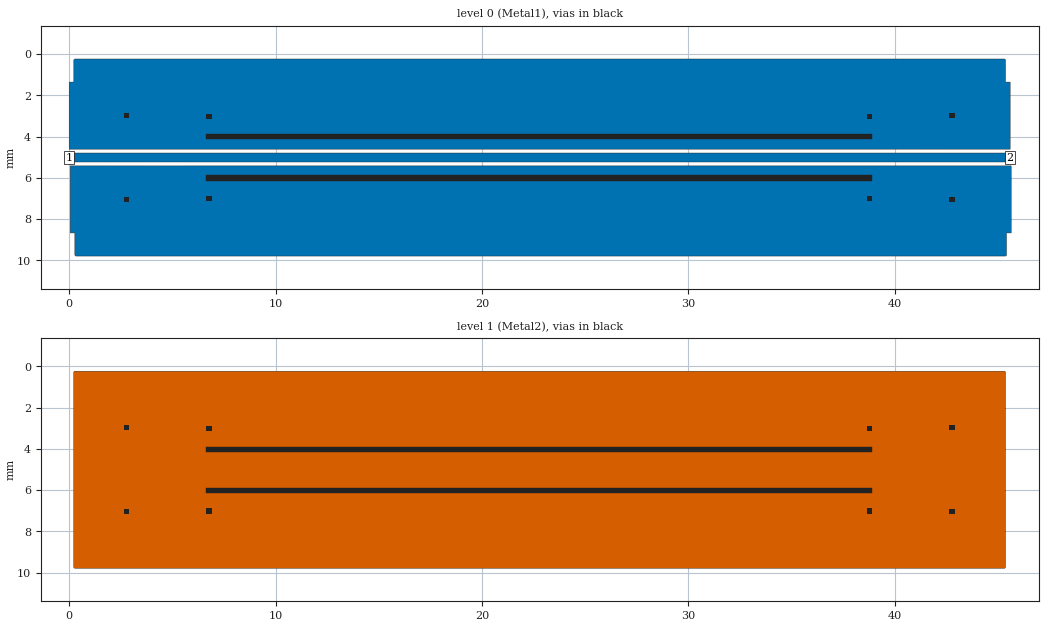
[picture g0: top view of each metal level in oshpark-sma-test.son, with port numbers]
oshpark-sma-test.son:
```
FTYP SONPROJ 17 ! Sonnet Project File
VER 17.52.2
HEADER
LIC antikernel2.1.48685 90e2ba8817c0 havequick azonenberg
DAT 05/13/2020 22:04:07
BUILT_BY_CREATED dxf 17.52.2 05/01/2020 05:35:06
BUILT_BY_SAVED sonnet 17.52.2
MDATE 05/13/2020 22:04:07
HDATE 05/13/2020 22:04:07
ANN Created by dxfgeo, Sonnet Software Inc.
END HEADER
DIM
ANG DEG
CAP PF
CON /OH
FREQ GHZ
IND NH
LNG MM
RES OH
END DIM
CONTROL
VARSWP
OPTIONS  -dj
SPEED 1
CACHE_ABS 1
Q_ACC N
END CONTROL
GEO
SYM
TMET "Free Space" 0 FREESPACE 376.7303136 0 0 0
BMET "Free Space" 0 FREESPACE 376.7303136 0 0 0
MET "Unknown_metal" 1 NOR INF 0.5 0 
MET "Copper 1oz thick" 2 TMM 58000000 0.5 0.035 2
MET "Nickel " 3 TMM 14300000 0.5 0.035 2
MET "Copper 0.5oz" 1 NOR 58000000 0.5 0.017 
MET "Unknown_metal" 1 VOL INF 0
BRI "Alumina (96%)" 0 9.4 0.0004 0 
BRI "Alumina (99.5%)" 0 9.9 0.0001 0 
BRI "Aluminum Nitride" 0 8.6 0.0003 0 
BRI "Arlon 25FR" 0 3.58 0.0035 0 
BRI "Arlon 25N" 0 3.38 0.0025 0 
BRI "Arlon AD5" 0 5.1 0.003 0 
BRI "Arlon AD10" 0 10.2 0.005 0 
BRI "Arlon AD250" 0 2.5 0.0018 0 
BRI "Arlon AD255A" 0 2.55 0.0015 0 
BRI "Arlon AD260A" 0 2.6 0.0018 0 
BRI "Arlon AD270" 0 2.7 0.0023 0 
BRI "Arlon AD300A" 0 3 0.002 0 
BRI "Arlon AD320A" 0 3.2 0.0032 0 
BRI "Arlon AD350A" 0 3.5 0.003 0 
BRI "Arlon AD410" 0 4.1 0.003 0 
BRI "Arlon AD430" 0 4.3 0.003 0 
BRI "Arlon AD450" 0 4.5 0.0035 0 
BRI "Arlon AD600" 0 6.15 0.003 0 
BRI "Arlon AD1000" 0 10.2 0.0023 0 
BRI "Arlon AR1000" 0 9.8 0.003 0 
BRI "Arlon CLTE" 0 2.96 0.0023 0 
BRI "Arlon CLTE-AT" 0 3 0.0013 0 
BRI "Arlon CLTE-P" 0 2.94 0.0025 0 
BRI "Arlon CLTE-XT" 0 2.94 0.0012 0 
BRI "Arlon Cu 217LX" 0 2.17 0.0009 0 
BRI "Arlon Cu 233LX" 0 2.33 0.0013 0 
BRI "Arlon Cu 250GT" 0 2.5 0.001 0 
BRI "Arlon Cu 250GX" 0 2.5 0.0018 0 
BRI "Arlon Cu 6250" 0 2.32 0.0013 0 
BRI "Arlon Cu 6700" 0 2.35 0.0025 0 
BRI "Arlon Di 522" 0 2.5 0.001 0 
BRI "Arlon Di 527" 0 2.5 0.0018 0 
BRI "Arlon Di 870" 0 2.33 0.0013 0 
BRI "Arlon Di 880" 0 2.17 0.0009 0 
BRI "Arlon Iso 917" 0 2.17 0.0013 0 
BRI "Arlon Iso 933" 0 2.33 0.0016 0 
BRI "Arlon Multi HF" 0 3.7 0.004 0 
BRI "Arlon TC350" 0 3.5 0.002 0 
BRI "Arlon TC600" 0 6.15 0.002 0 
BRI "Beryllia (99.5%)" 0 6.5 0.0004 0 
BRI "CEM-1" 0 4.5 0.02 0 
BRI "CEM-3" 0 4.5 0.02 0 
BRI "Dupont 9K7" 0 7.1 0.0012 0 
BRI "Dupont 943" 0 7.4 0.002 0 
BRI "Dupont 951" 0 7.8 0.006 0 
BRI "Dupont FEP" 0 2 0.0005 0 
BRI "Dupont Vacrel" 0 3.8 0.011 0 
BRI "ESL 41010" 0 7.5 0.005 0 
BRI "ESL 41020" 0 7.25 0.005 0 
BRI "ESL 41050" 0 13.5 0.002 0 
BRI "ESL 41060" 0 16.5 0.002 0 
BRI "ESL 41110" 0 4.5 0.004 0 
BRI "Ferro A6M" 0 5.9 0.002 0 
BRI "Ferro A6S" 0 5.9 0.002 0 
BRI "Ferro L8" 0 7.3 0.0018 0 
BRI "FR-4" 0 4.4 0.02 0 
BRI "G-10" 0 4.8 0.025 0 
BRI "Gallium Arsenide" 0 12.9 0.006 0 
BRI "Gallium Nitride" 0 9.7 0 0 
BRI "Glass (Pyrex)" 0 4.82 0.0054 0 
BRI "Heraeus HL2000" 0 7.3 0.0026 0 
BRI "Isola 370HR" 0 4.04 0.021 0 
BRI "Isola FR408" 0 3.77 0.0116 0 
BRI "Isola FR408HR" 0 3.68 0.0092 0 
BRI "Isola Getek" 0 3.6 0.01 0 
BRI "Isola GI-180" 0 3.7 0.013 0 
BRI "Isola IS415" 0 3.82 0.0125 0 
BRI "Isola IS620i" 0 3.58 0.006 0 
BRI "Isola IS680-280" 0 2.8 0.0025 0 
BRI "Isola IS680-300" 0 3 0.003 0 
BRI "Isola IS680-320" 0 3.2 0.003 0 
BRI "Isola IS680-333" 0 3.33 0.003 0 
BRI "Isola IS680-338" 0 3.38 0.0032 0 
BRI "Isola IS680-345" 0 3.45 0.0036 0 
BRI "Kerafol CT800" 0 5.3 0.008 0 
BRI "Nelco MW9350" 0 3.7 0.004 0 
BRI "Nelco N4000-12" 0 3.7 0.008 0 
BRI "Nelco N4000-13" 0 3.7 0.009 0 
BRI "Nelco N4000-13SI" 0 3.2 0.007 0 
BRI "Nelco N4000-13EP" 0 3.7 0.008 0 
BRI "Nelco N4350-13RF" 0 3.5 0.0065 0 
BRI "Nelco N4380-13RF" 0 3.8 0.007 0 
BRI "Nelco N9300-13RF" 0 3 0.004 0 
BRI "Nelco N9320-13RF" 0 3.2 0.0045 0 
BRI "Nelco N9338-13RF" 0 3.38 0.0046 0 
BRI "Nelco N9350-13RF" 0 3.48 0.0055 0 
BRI "Nelco NH9294" 0 2.94 0.0022 0 
BRI "Nelco NH9300" 0 3 0.0023 0 
BRI "Nelco NH9320" 0 3.2 0.0024 0 
BRI "Nelco NH9338" 0 3.38 0.0025 0 
BRI "Nelco NH9348" 0 3.48 0.003 0 
BRI "Nelco NH9350" 0 3.5 0.003 0 
BRI "Nelco NH9410" 0 4.1 0.003 0 
BRI "Nelco NH9450" 0 4.5 0.003 0 
BRI "Nelco NX9240" 0 2.4 0.0016 0 
BRI "Nelco NX9245" 0 2.45 0.0016 0 
BRI "Nelco NX9250" 0 2.5 0.0017 0 
BRI "Nelco NX9255" 0 2.55 0.0018 0 
BRI "Nelco NX9260" 0 2.6 0.0019 0 
BRI "Nelco NY9208" 0 2.08 0.0006 0 
BRI "Nelco NY9217" 0 2.17 0.0008 0 
BRI "Nelco NY9220" 0 2.2 0.0009 0 
BRI "Nelco NY9233" 0 2.33 0.0011 0 
BRI "PET" 0 3.37 0.0208 0 
BRI "Polyimide" 0 3.5 0.003 0 
BRI "Quartz (Fused)" 0 3.78 0.0001 0 
BRI "Rogers 3001" 0 2.28 0.003 0 
BRI "Rogers RO2808" 0 7.6 0.0015 0 
BRI "Rogers RO3003" 0 3 0.0013 0 
BRI "Rogers RO3006" 0 6.5 0.002 0 
BRI "Rogers RO3010" 0 11.2 0.0022 0 
BRI "Rogers RO3035" 0 3.6 0.0018 0 
BRI "Rogers RO3203" 0 3.02 0.0016 0 
BRI "Rogers RO3206" 0 6.6 0.0027 0 
BRI "Rogers RO3210" 0 10.8 0.0027 0 
BRI "Rogers RO3730" 0 3 0.0016 0 
BRI "Rogers RO4003C" 0 3.55 0.0029 0 
BRI "Rogers RO4533" 0 3.45 0.0029 0 
BRI "Rogers RO4534" 0 3.4 0.003 0 
BRI "Rogers RO4350B" 0 3.66 0.0037 0 
BRI "Rogers RO4350BTX" 0 3.66 0.0034 0 
BRI "Rogers RO4360" 0 6.15 0.0038 0 
BRI "Rogers RO4450B-3.6" 0 3.3 0.0043 0 
BRI "Rogers RO4450B-4" 0 3.54 0.004 0 
BRI "Rogers RO4450F" 0 3.52 0.0041 0 
BRI "Rogers RO4730" 0 3 0.0033 0 
BRI "Rogers RT5870" 0 2.33 0.0012 0 
BRI "Rogers RT5880" 0 2.2 0.0009 0 
BRI "Rogers RT5880LZ" 0 1.96 0.0019 0 
BRI "Rogers RT6002" 0 2.94 0.0012 0 
BRI "Rogers RT6006" 0 6.15 0.0027 0 
BRI "Rogers RT6010LM" 0 10.9 0.0023 0 
BRI "Rogers RT6035HTC" 0 3.6 0.0013 0 
BRI "Rogers RT6202" 0 2.94 0.0015 0 
BRI "Rogers RT6202PR" 0 2.95 0.0015 0 
BRI "Rogers Syron7000" 0 3.4 0.0045 0 
BRI "Rogers Syron7100-2" 0 3.61 0.006 0 
BRI "Rogers Syron7100-4" 0 3.39 0.005 0 
BRI "Rogers Theta" 0 4.01 0.0118 0 
BRI "Rogers TMM 3" 0 3.39 0.002 0 
BRI "Rogers TMM 4" 0 4.5 0.002 0 
BRI "Rogers TMM 6" 0 6 0.0023 0 
BRI "Rogers TMM 10" 0 9.56 0.0022 0 
BRI "Rogers TMM 10i" 0 9.96 0.002 0 
BRI "Rogers UL2000" 0 2.5 0.0019 0 
BRI "Rogers UL3850" 0 3.05 0.0025 0 
BRI "Rogers UL3908" 0 2.9 0.0025 0 
BRI "Rogers XT8000" 0 3.34 0.0035 0 
BRI "Rogers XT8100-2" 0 3.54 0.0049 0 
BRI "Rogers XT8100-4" 0 3.32 0.0038 0 
BRI "Silicon (intrinsic)" 0 11.9 0.004 0.00044 
BRI "Silicon Dioxide" 0 3.9 0 0 
BRI "Silicon Nitride" 0 7.5 0 0 
BRI "Taconic CER-10" 0 10 0.0035 0 
BRI "Taconic FastFilm" 0 2.7 0.0012 0 
BRI "Taconic Fastrise-DS" 0 2.96 0.0018 0 
BRI "Taconic Fastrise27" 0 2.7 0.0014 0 
BRI "Taconic Fastrise77" 0 7.7 0.0034 0 
BRI "Taconic FEP" 0 2 0.0003 0 
BRI "Taconic RF-30" 0 3 0.0014 0 
BRI "Taconic RF-35" 0 3.5 0.0018 0 
BRI "Taconic RF-35A2" 0 3.5 0.0011 0 
BRI "Taconic RF-35P" 0 3.5 0.0025 0 
BRI "Taconic RF-41" 0 4.1 0.0038 0 
BRI "Taconic RF-43" 0 4.3 0.0033 0 
BRI "Taconic RF-45" 0 4.5 0.0037 0 
BRI "Taconic RF-60A" 0 6.15 0.0038 0 
BRI "Taconic RF-301" 0 2.97 0.0012 0 
BRI "Taconic TacBond HT" 0 2.35 0.0025 0 
BRI "Taconic TLA-6" 0 2.62 0.0012 0 
BRI "Taconic TLC-27" 0 2.75 0.003 0 
BRI "Taconic TLC-30" 0 3 0.003 0 
BRI "Taconic TLC-32" 0 3.2 0.003 0 
BRI "Taconic TLE-95" 0 2.95 0.0028 0 
BRI "Taconic TLF-34" 0 3.4 0.002 0 
BRI "Taconic TLF-35" 0 3.5 0.002 0 
BRI "Taconic TLP-3" 0 2.33 0.0009 0 
BRI "Taconic TLP-5" 0 2.2 0.0009 0 
BRI "Taconic TLP-5A" 0 2.17 0.0009 0 
BRI "Taconic TLT-0" 0 2.45 0.0006 0 
BRI "Taconic TLT-9" 0 2.5 0.0006 0 
BRI "Taconic TLT-8" 0 2.55 0.0006 0 
BRI "Taconic TLT-7" 0 2.6 0.0006 0 
BRI "Taconic TLT-6" 0 2.65 0.0006 0 
BRI "Taconic TLX-0" 0 2.45 0.0019 0 
BRI "Taconic TLX-9" 0 2.5 0.0019 0 
BRI "Taconic TLX-8" 0 2.55 0.0019 0 
BRI "Taconic TLX-7" 0 2.6 0.0019 0 
BRI "Taconic TLX-6" 0 2.65 0.0019 0 
BRI "Taconic TLY-3" 0 2.33 0.0009 0 
BRI "Taconic TLY-3F" 0 2.33 0.0009 0 
BRI "Taconic TLY-5" 0 2.2 0.0009 0 
BRI "Taconic TLY-5-L" 0 2.2 0.0009 0 
BRI "Taconic TLY-5A" 0 2.17 0.0009 0 
BRI "Taconic TLY-5A-L" 0 2.17 0.0009 0 
BRI "Taconic TPG-30" 0 3 0.0038 0 
BRI "Taconic TPG-32" 0 3.2 0.005 0 
BRI "Taconic TPG-35" 0 3.5 0.005 0 
BRI "Taconic TRF-41" 0 4.1 0.0035 0 
BRI "Taconic TRF-43" 0 4.3 0.0035 0 
BRI "Taconic TRF-45" 0 4.5 0.0035 0 
BRI "Taconic TSM-DS" 0 2.85 0.001 0 
BRI "Taconic TSM-DS3" 0 3 0.0011 0 
BRI "Taconic TSM-26" 0 2.6 0.0014 0 
BRI "Taconic TSM-29" 0 2.94 0.0013 0 
BRI "Taconic TSM-30" 0 3 0.0013 0 
BRI "Teflon (PTFE)" 0 2.08 0.0004 0 
BOX 2 45.6 10 1824 400 20 0
      1 1 1 0 0 0 0 "Air"
      0.16 3.6 1 0.0092 0 0 0 "Isola FR408HR"
      1 1 1 0 0 0 0 "Air"
TECHLAY METAL Metal1 <UNSPECIFIED> -2 0 
0 0 1 N 974 1 1 100 100 0 0 0 Y
END
END
TECHLAY METAL Metal2 <UNSPECIFIED> -3 0 
1 0 3 N 976 1 1 100 100 0 0 0 Y
END
END
TECHLAY VIA Via1 <UNSPECIFIED> -4 0 
VIA POLYGON
1 0 -1 N 0 1 1 100 100 0 0 0 Y
TOLEVEL 0 RING NOCOVERS
END
END
LORGN 0 10 U 
POR1 BOX
POLY 946 1
0
1 50 0 0 0 -1.498801083e-15 5.014998474 
POR1 BOX
POLY 946 1
2
2 50 0 0 0 45.6000061 5.014998474 
NUM 14
0 49 1 N 949 1 1 100 100 0 0 0 Y
TLAYNAM Metal1 INH
45.31300354 0.239996948
0.28700256 0.239996948
0.28200531 0.24059967
0.27600098 0.241095581
0.27000427 0.242896118
0.26399994 0.244597473
0.25800323 0.247496643
0.25300598 0.250197449
0.2480011 0.254096069
0.2440033 0.257796326
0.24000549 0.262702026
0.23600006 0.26719574
0.23300171 0.272696533
0.23000336 0.27789978
0.22800446 0.283896484
0.22600555 0.28949646
0.22600555 0.295699158
0.2250061 0.30159668
0.2250061 1.359999695
-1.498801083e-15 1.359999695
-1.498801083e-15 4.609999695
5.6000061 4.609999695
5.60700226 4.609702148
5.60900116 4.609702148
5.61199951 4.609999695
39.98699951 4.609999695
39.99000549 4.609702148
39.99200439 4.609801331
40 4.609000244
45.6000061 4.609999695
45.6000061 1.359999695
45.375 1.359999695
45.375 0.302496948
45.37400818 0.296599426
45.37400818 0.290801086
45.37200928 0.284697571
45.37001038 0.279097595
45.36799622 0.27349762
45.36500549 0.268302002
45.36100769 0.263396301
45.35700989 0.258795776
45.352005 0.254698792
45.3480072 0.250899353
45.3420105 0.247901001
45.33700562 0.245101013
45.33100891 0.243201294
45.32499695 0.241400757
45.31900024 0.240698853
45.31300354 0.239996948
END
0 5 1 N 946 1 1 100 100 0 0 0 Y
TLAYNAM Metal1 INH
-1.498801083e-15 4.809996643
-1.498801083e-15 5.220000305
45.6000061 5.220000305
45.6000061 4.809996643
-1.498801083e-15 4.809996643
END
0 49 1 N 945 1 1 100 100 0 0 0 Y
TLAYNAM Metal1 INH
5.6500061 5.420996704
0.05 5.419997253
0.05 8.66999725
0.2750061 8.66999725
0.2750061 9.7275
0.27600555 9.73339752
0.27600555 9.73919586
0.27800446 9.74529938
0.28000336 9.75089935
0.28200226 9.75649933
0.28500061 9.76169495
0.28900604 9.76660065
0.29300385 9.77120117
0.2980011 9.77529816
0.30200653 9.7790976
0.30800323 9.78209595
0.31300049 9.78489594
0.31900482 9.78679565
0.32500153 9.78859619
0.33100586 9.7892981
0.33700256 9.79
45.36199646 9.79
45.36800842 9.78939728
45.37400513 9.78890137
45.38000183 9.78710083
45.38599854 9.78539948
45.3920105 9.78250031
45.39700012 9.7797995
45.402005 9.77590088
45.40600281 9.77220062
45.41000061 9.76729492
45.41399841 9.76280121
45.41700439 9.75730042
45.42001038 9.75209717
45.42200928 9.74610046
45.42400818 9.74050049
45.42400818 9.73429779
45.425 9.72840027
45.425 8.66999725
45.6500061 8.66999725
45.6500061 5.419997253
40.05 5.419997253
40.04299622 5.4202948
40.04099731 5.4202948
40.03800659 5.419997253
5.66300659 5.419997253
5.66000061 5.4202948
5.65800171 5.420195618
5.6500061 5.420996704
END
1 69 3 N 963 1 1 100 100 0 0 0 Y
TLAYNAM Metal2 INH
USER_DAT FromImport
45.31114807 0.2346405
0.28514707 0.2346405
0.28014987 0.23524323
0.27414547 0.23573914
0.26814877 0.23753967
0.26214447 0.23924103
0.25614777 0.2421402
0.25115047 0.244841
0.24614557 0.24873963
0.24214777 0.25243988
0.23814997 0.25734558
0.23414457 0.2618393
0.23114627 0.26734009
0.22814787 0.27254334
0.22614897 0.27854004
0.22415007 0.28414002
0.22415007 0.29034271
0.22315067 0.29624024
0.22315067 9.72214353
0.22415007 9.72804103
0.22415007 9.73383943
0.22614897 9.73994293
0.22814787 9.74554293
0.23014677 9.75114293
0.23314517 9.75633853
0.23715057 9.76124423
0.24114837 9.76584473
0.24614557 9.76994173
0.25015107 9.77374113
0.25614777 9.77673953
0.26114497 9.77953953
0.26714937 9.78143923
0.27314607 9.78323973
0.27915037 9.78394163
0.28514707 9.78464353
45.31014097 9.78464353
45.31615297 9.78404083
45.32214967 9.78354493
45.32814637 9.78174443
45.33414307 9.78004303
45.34015497 9.77714383
45.34514467 9.77444303
45.35014957 9.77054443
45.35414737 9.76684413
45.35814517 9.76193843
45.36214297 9.75744473
45.36514887 9.75194393
45.36815487 9.74674073
45.37015377 9.74074403
45.37215267 9.73514403
45.37215267 9.72894133
45.37314447 9.72304383
45.37314447 0.2971405
45.37215267 0.29124298
45.37215267 0.28544464
45.37015377 0.27934113
45.36815487 0.27374115
45.36614077 0.26814118
45.36314997 0.26294556
45.35915217 0.25803986
45.35515437 0.25343933
45.35014957 0.24934235
45.34615177 0.24554291
45.34015497 0.24254456
45.33515017 0.23974457
45.32915347 0.23784485
45.32314147 0.23604431
45.31714477 0.23534241
45.31114807 0.2346405
END
VIA POLYGON
1 5 -1 N 953 1 1 100 100 0 0 0 Y
TOLEVEL 0 RING NOCOVERS
TLAYNAM Via1 INH
USER_DAT FromImport
42.65424652 3.104654541
42.65424652 2.854654541
42.90424652 2.854654541
42.90424652 3.104654541
42.65424652 3.104654541
END
VIA POLYGON
1 5 -1 N 954 1 1 100 100 0 0 0 Y
TOLEVEL 0 RING NOCOVERS
TLAYNAM Via1 INH
USER_DAT FromImport
2.65424652 3.104654541
2.65424652 2.854654541
2.90424652 2.854654541
2.90424652 3.104654541
2.65424652 3.104654541
END
VIA POLYGON
1 5 -1 N 955 1 1 100 100 0 0 0 Y
TOLEVEL 0 RING NOCOVERS
TLAYNAM Via1 INH
USER_DAT FromImport
42.65424652 7.164652099
42.65424652 6.914652099
42.90424652 6.914652099
42.90424652 7.164652099
42.65424652 7.164652099
END
VIA POLYGON
1 5 -1 N 956 1 1 100 100 0 0 0 Y
TOLEVEL 0 RING NOCOVERS
TLAYNAM Via1 INH
USER_DAT FromImport
2.65424652 7.164652099
2.65424652 6.914652099
2.90424652 6.914652099
2.90424652 7.164652099
2.65424652 7.164652099
END
VIA POLYGON
1 5 -1 N 957 1 1 100 100 0 0 0 Y
TOLEVEL 0 RING NOCOVERS
TLAYNAM Via1 INH
USER_DAT FromImport
6.65424652 7.13465332
6.65424652 6.88465332
6.90424652 6.88465332
6.90424652 7.13465332
6.65424652 7.13465332
END
VIA POLYGON
1 5 -1 N 958 1 1 100 100 0 0 0 Y
TOLEVEL 0 RING NOCOVERS
TLAYNAM Via1 INH
USER_DAT FromImport
6.65424652 3.13465332
6.65424652 2.88465332
6.90424652 2.88465332
6.90424652 3.13465332
6.65424652 3.13465332
END
VIA POLYGON
1 5 -1 N 959 1 1 100 100 0 0 0 Y
TOLEVEL 0 RING NOCOVERS
TLAYNAM Via1 INH
USER_DAT FromImport
38.65424652 7.13465332
38.65424652 6.88465332
38.90424652 6.88465332
38.90424652 7.13465332
38.65424652 7.13465332
END
VIA POLYGON
1 5 -1 N 960 1 1 100 100 0 0 0 Y
TOLEVEL 0 RING NOCOVERS
TLAYNAM Via1 INH
USER_DAT FromImport
38.65424652 3.13465332
38.65424652 2.88465332
38.90424652 2.88465332
38.90424652 3.13465332
38.65424652 3.13465332
END
VIA POLYGON
1 5 -1 N 961 1 1 100 100 0 0 0 Y
TOLEVEL 0 RING NOCOVERS
TLAYNAM Via1 INH
USER_DAT FromImport
6.65424652 6.13465332
6.65424652 5.88465332
38.9082489 5.88465332
38.9082489 6.13465332
6.65424652 6.13465332
END
VIA POLYGON
1 5 -1 N 962 1 1 100 100 0 0 0 Y
TOLEVEL 0 RING NOCOVERS
TLAYNAM Via1 INH
USER_DAT FromImport
6.65424652 4.13465332
6.65424652 3.88465332
38.92311096 3.88465332
38.92311096 4.13465332
6.65424652 4.13465332
END
END GEO
OPT
MAX 100
END OPT
VARSWP
ENABLED Y
FREQ Y AY ABS_ENTRY 0.1 6.0 -1 300 
END
END VARSWP
```
